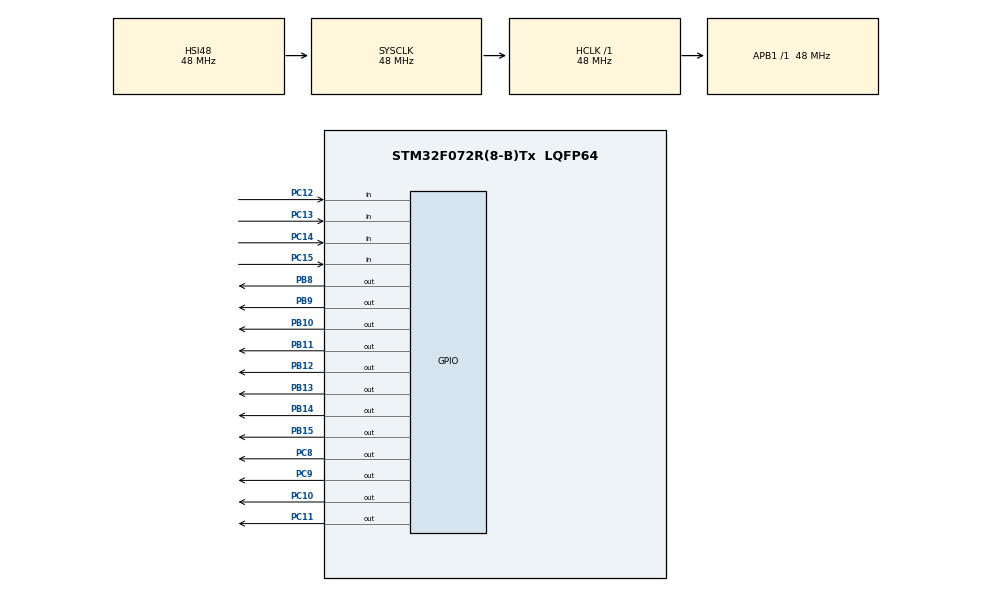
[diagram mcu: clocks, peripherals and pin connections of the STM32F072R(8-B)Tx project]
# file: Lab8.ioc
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Mcu.Family=STM32F0
Mcu.Name=STM32F072R(8-B)Tx
Mcu.Package=LQFP64
NVIC.TIM3_IRQn=true\:0\:0\:false\:false\:true\:true\:true
PB10.Signal=GPIO_Output
PB11.Signal=GPIO_Output
PB12.Signal=GPIO_Output
PB13.Signal=GPIO_Output
PB14.Signal=GPIO_Output
PB15.Signal=GPIO_Output
PB8.Signal=GPIO_Output
PB9.Signal=GPIO_Output
PC10.Signal=GPIO_Output
PC11.Signal=GPIO_Output
PC12.GPIO_PuPd=GPIO_PULLUP
PC12.Signal=GPIO_Input
PC13.GPIO_PuPd=GPIO_PULLUP
PC13.Signal=GPIO_Input
PC14-OSC32_IN.GPIO_PuPd=GPIO_PULLUP
PC14-OSC32_IN.Signal=GPIO_Input
PC15-OSC32_OUT.Signal=GPIO_Input
PC8.Signal=GPIO_Output
PC9.Signal=GPIO_Output
PF0-OSC_IN.Mode=HSE-External-Oscillator
PF0-OSC_IN.Signal=RCC_OSC_IN
PF1-OSC_OUT.Mode=HSE-External-Oscillator
PF1-OSC_OUT.Signal=RCC_OSC_OUT
ProjectManager.HeapSize=0x200
ProjectManager.StackSize=0x400
ProjectManager.TargetToolchain=MDK-ARM V5
RCC.AHBFreq_Value=48000000
RCC.APB1Freq_Value=48000000
RCC.APB1TimFreq_Value=48000000
RCC.HCLKFreq_Value=48000000
RCC.SYSCLKFreq_VALUE=48000000
RCC.SYSCLKSource=RCC_SYSCLKSOURCE_HSI48
TIM3.ClockDivision=TIM_CLOCKDIVISION_DIV1
TIM3.Period=1
TIM3.Prescaler=47999
VP_TIM3_VS_ClockSourceINT.Mode=Internal
board=custom

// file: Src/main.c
/* USER CODE BEGIN Header */
/**
  ******************************************************************************
  * @file           : main.c
  * @brief          : Main program body
  ******************************************************************************
  * @attention
  *
  * <h2><center>&copy; Copyright (c) 2022 STMicroelectronics.
  * All rights reserved.</center></h2>
  *
  * This software component is licensed by ST under BSD 3-Clause license,
  * the "License"; You may not use this file except in compliance with the
  * License. You may obtain a copy of the License at:
  *                        opensource.org/licenses/BSD-3-Clause
  *
  ******************************************************************************
  */
/* USER CODE END Header */

#include "main.h"

TIM_HandleTypeDef htim3;

void SystemClock_Config(void);
static void MX_GPIO_Init(void);
static void MX_TIM3_Init(void);

int Number[10] = {
	0xFC00, 0x6000, 0xDA00,
	0xF200, 0x6600, 0xB600,
	0xBE00, 0xE000, 0xFE00,
	0xE600
};

enum KeyCode {

	KEY_0,
	KEY_1, KEY_2, KEY_3,
	KEY_4, KEY_5, KEY_6,
	KEY_7, KEY_8, KEY_9,
	KEY_A, KEY_B, KEY_C, KEY_D,
	KEY_ASTERISK, KEY_HASH,
	KEY_UNDEFINED
};

int translateKeyCodeToLED(enum KeyCode code){
	if((int) code < 10)
		return Number[(int) code];
	else if(code == KEY_A)
		return 0xEE00;
	else if(code == KEY_B)
		return 0x3E00;
	else if(code == KEY_C)
        //0001 1010
		return 0x1A00;
	else if(code == KEY_D)
			// 0111 1010
		return 0x7A00;
	else if(code == KEY_ASTERISK)
		//1001 1110
		return 0x9E00;
	else if(code == KEY_HASH)
		//1000 1110
		return 0x8E00;
	else
		return 0x9000;
}

enum KeyCode scanKey(int row){
	switch (row){
		case 0: {
			if(HAL_GPIO_ReadPin(GPIOC, GPIO_PIN_12) == 0) return KEY_1;
			else if(HAL_GPIO_ReadPin(GPIOC, GPIO_PIN_13) == 0) return KEY_2;
			else if(HAL_GPIO_ReadPin(GPIOC, GPIO_PIN_14) == 0) return KEY_3;
			else if(HAL_GPIO_ReadPin(GPIOC, GPIO_PIN_15) == 0) return KEY_A;
			else return KEY_UNDEFINED;
		}
		case 1: {
			if(HAL_GPIO_ReadPin(GPIOC, GPIO_PIN_12) == 0) return KEY_4;
			else if(HAL_GPIO_ReadPin(GPIOC, GPIO_PIN_13) == 0) return KEY_5;
			else if(HAL_GPIO_ReadPin(GPIOC, GPIO_PIN_14) == 0) return KEY_6;
			else if(HAL_GPIO_ReadPin(GPIOC, GPIO_PIN_15) == 0) return KEY_B;
			else return KEY_UNDEFINED;
		}
		case 2: {
			if(HAL_GPIO_ReadPin(GPIOC, GPIO_PIN_12) == 0) return KEY_7;
			else if(HAL_GPIO_ReadPin(GPIOC, GPIO_PIN_13) == 0) return KEY_8;
			else if(HAL_GPIO_ReadPin(GPIOC, GPIO_PIN_14) == 0) return KEY_9;
			else if(HAL_GPIO_ReadPin(GPIOC, GPIO_PIN_15) == 0) return KEY_C;
			else return KEY_UNDEFINED;
		}
		case 3: {
			if(HAL_GPIO_ReadPin(GPIOC, GPIO_PIN_12) == 0) return KEY_ASTERISK;
			else if(HAL_GPIO_ReadPin(GPIOC, GPIO_PIN_13) == 0) return KEY_0;
			else if(HAL_GPIO_ReadPin(GPIOC, GPIO_PIN_14) == 0) return KEY_HASH;
			else if(HAL_GPIO_ReadPin(GPIOC, GPIO_PIN_15) == 0) return KEY_D;
			else return KEY_UNDEFINED;
		}
		default: {
			return KEY_UNDEFINED;
		}
	}
}

volatile int value = 9995;
enum KeyCode lastKeyOfRow[4] = {KEY_UNDEFINED};
enum KeyCode currentKeyOfRow[4] = {KEY_UNDEFINED};
int64_t keyLastUpdate = 0L;

volatile int scanningIndex = 0;
volatile int displayArray[4] = {0,0,0,0};

void HAL_TIM_PeriodElapsedCallback(TIM_HandleTypeDef *htim){
	if(htim->Instance != TIM3) return;

	// Reset Scan Lines -> GPIOC 8 ~ 11
	HAL_GPIO_WritePin(GPIOC, 0x0F00, GPIO_PIN_SET);
	// Reset LED Lines
	HAL_GPIO_WritePin(GPIOB, 0xFF00, GPIO_PIN_RESET);

	// Set Current Scan Line (From PC8 to PC11)
	// 0000 1111 0000 0000
	HAL_GPIO_WritePin(GPIOC, 0x0100 << scanningIndex, GPIO_PIN_RESET);
	enum KeyCode keycode = scanKey(scanningIndex);

	//Debounce
	if(keycode != lastKeyOfRow[scanningIndex]){
			keyLastUpdate = HAL_GetTick();
	}

	if((HAL_GetTick() - keyLastUpdate) > 70){
				if(keycode != currentKeyOfRow[scanningIndex]){
					currentKeyOfRow[scanningIndex] = keycode;
					if(keycode != KEY_UNDEFINED){

						// Button Action
						 for (int i = 4; i > 0; i--) {
							  if(i == 4) continue;
							  else displayArray[i] = displayArray[i - 1];
							}
							displayArray[0] = translateKeyCodeToLED(keycode);
						// Button Action End
					}
				}
			}

			lastKeyOfRow[scanningIndex] = keycode;
			//Debounce End

			//
			// Do Display
			//
		HAL_GPIO_WritePin(GPIOB, 0xFF00, GPIO_PIN_RESET);
		HAL_GPIO_WritePin(GPIOB, displayArray[scanningIndex], GPIO_PIN_SET);

		scanningIndex++;
		if(scanningIndex >= 4) scanningIndex = 0;

}

int main(void)
{

  /* MCU Configuration--------------------------------------------------------*/

  /* Reset of all peripherals, Initializes the Flash interface and the Systick. */
  HAL_Init();

  /* Configure the system clock */
  SystemClock_Config();

  /* Initialize all configured peripherals */
  MX_GPIO_Init();
  MX_TIM3_Init();

  /* Infinite loop */
  /* USER CODE BEGIN WHILE */

	HAL_TIM_Base_Start_IT(&htim3);

  while (1)
  {
    /* USER CODE END WHILE */

  }
}

void SystemClock_Config(void)
{
  RCC_OscInitTypeDef RCC_OscInitStruct = {0};
  RCC_ClkInitTypeDef RCC_ClkInitStruct = {0};

  /** Initializes the CPU, AHB and APB busses clocks
  */
  RCC_OscInitStruct.OscillatorType = RCC_OSCILLATORTYPE_HSI48;
  RCC_OscInitStruct.HSI48State = RCC_HSI48_ON;
  RCC_OscInitStruct.PLL.PLLState = RCC_PLL_NONE;
  if (HAL_RCC_OscConfig(&RCC_OscInitStruct) != HAL_OK)
  {
    Error_Handler();
  }
  /** Initializes the CPU, AHB and APB busses clocks
  */
  RCC_ClkInitStruct.ClockType = RCC_CLOCKTYPE_HCLK|RCC_CLOCKTYPE_SYSCLK
                              |RCC_CLOCKTYPE_PCLK1;
  RCC_ClkInitStruct.SYSCLKSource = RCC_SYSCLKSOURCE_HSI48;
  RCC_ClkInitStruct.AHBCLKDivider = RCC_SYSCLK_DIV1;
  RCC_ClkInitStruct.APB1CLKDivider = RCC_HCLK_DIV1;

  if (HAL_RCC_ClockConfig(&RCC_ClkInitStruct, FLASH_LATENCY_1) != HAL_OK)
  {
    Error_Handler();
  }
}

static void MX_TIM3_Init(void)
{

  TIM_ClockConfigTypeDef sClockSourceConfig = {0};
  TIM_MasterConfigTypeDef sMasterConfig = {0};

  htim3.Instance = TIM3;
  htim3.Init.Prescaler = 47999;
  htim3.Init.CounterMode = TIM_COUNTERMODE_UP;
  htim3.Init.Period = 1;
  htim3.Init.ClockDivision = TIM_CLOCKDIVISION_DIV1;
  htim3.Init.AutoReloadPreload = TIM_AUTORELOAD_PRELOAD_DISABLE;
  if (HAL_TIM_Base_Init(&htim3) != HAL_OK)
  {
    Error_Handler();
  }
  sClockSourceConfig.ClockSource = TIM_CLOCKSOURCE_INTERNAL;
  if (HAL_TIM_ConfigClockSource(&htim3, &sClockSourceConfig) != HAL_OK)
  {
    Error_Handler();
  }
  sMasterConfig.MasterOutputTrigger = TIM_TRGO_RESET;
  sMasterConfig.MasterSlaveMode = TIM_MASTERSLAVEMODE_DISABLE;
  if (HAL_TIMEx_MasterConfigSynchronization(&htim3, &sMasterConfig) != HAL_OK)
  {
    Error_Handler();
  }

}

static void MX_GPIO_Init(void)
{
  GPIO_InitTypeDef GPIO_InitStruct = {0};

  /* GPIO Ports Clock Enable */
  __HAL_RCC_GPIOC_CLK_ENABLE();
  __HAL_RCC_GPIOB_CLK_ENABLE();

  /*Configure GPIO pin Output Level */
  HAL_GPIO_WritePin(GPIOB, GPIO_PIN_10|GPIO_PIN_11|GPIO_PIN_12|GPIO_PIN_13
                          |GPIO_PIN_14|GPIO_PIN_15|GPIO_PIN_8|GPIO_PIN_9, GPIO_PIN_RESET);

  /*Configure GPIO pin Output Level */
  HAL_GPIO_WritePin(GPIOC, GPIO_PIN_8|GPIO_PIN_9|GPIO_PIN_10|GPIO_PIN_11, GPIO_PIN_RESET);

  /*Configure GPIO pins : PC13 PC14 PC15 */
  GPIO_InitStruct.Pin = GPIO_PIN_13|GPIO_PIN_14|GPIO_PIN_15;
  GPIO_InitStruct.Mode = GPIO_MODE_INPUT;
  GPIO_InitStruct.Pull = GPIO_NOPULL;
  HAL_GPIO_Init(GPIOC, &GPIO_InitStruct);

  /*Configure GPIO pins : PB2 PB3 */
  GPIO_InitStruct.Pin = GPIO_PIN_2|GPIO_PIN_3;
  GPIO_InitStruct.Mode = GPIO_MODE_IT_RISING;
  GPIO_InitStruct.Pull = GPIO_NOPULL;
  HAL_GPIO_Init(GPIOB, &GPIO_InitStruct);

  /*Configure GPIO pins : PB10 PB11 PB12 PB13
                           PB14 PB15 PB8 PB9 */
  GPIO_InitStruct.Pin = GPIO_PIN_10|GPIO_PIN_11|GPIO_PIN_12|GPIO_PIN_13
                          |GPIO_PIN_14|GPIO_PIN_15|GPIO_PIN_8|GPIO_PIN_9;
  GPIO_InitStruct.Mode = GPIO_MODE_OUTPUT_PP;
  GPIO_InitStruct.Pull = GPIO_NOPULL;
  GPIO_InitStruct.Speed = GPIO_SPEED_FREQ_LOW;
  HAL_GPIO_Init(GPIOB, &GPIO_InitStruct);

  /*Configure GPIO pins : PC8 PC9 PC10 PC11 */
  GPIO_InitStruct.Pin = GPIO_PIN_8|GPIO_PIN_9|GPIO_PIN_10|GPIO_PIN_11;
  GPIO_InitStruct.Mode = GPIO_MODE_OUTPUT_PP;
  GPIO_InitStruct.Pull = GPIO_NOPULL;
  GPIO_InitStruct.Speed = GPIO_SPEED_FREQ_LOW;
  HAL_GPIO_Init(GPIOC, &GPIO_InitStruct);

  /* EXTI interrupt init*/
  HAL_NVIC_SetPriority(EXTI2_3_IRQn, 0, 0);
  HAL_NVIC_EnableIRQ(EXTI2_3_IRQn);

}

void Error_Handler(void)
{
}

/************************ (C) COPYRIGHT STMicroelectronics *****END OF FILE****/
